One B-rep face of a CAD part: STEP entity #7803.
In plain terms, the planar face has unit normal (0, 0, 1).
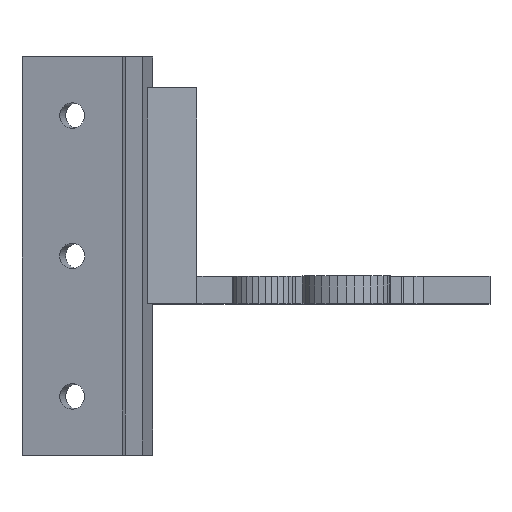
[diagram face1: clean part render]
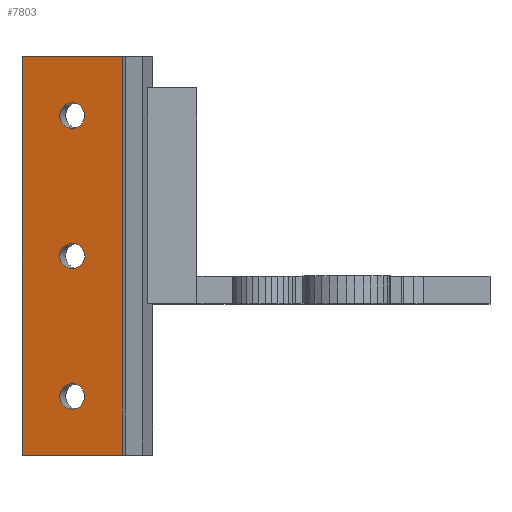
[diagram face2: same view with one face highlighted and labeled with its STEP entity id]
Its self-contained STEP definition (entity closure, numbers rounded to 3 decimals):
#7249 = VERTEX_POINT('',#7250);
#7250 = CARTESIAN_POINT('',(-9.3,-36.,5.));
#7257 = PLANE('',#7258);
#7258 = AXIS2_PLACEMENT_3D('',#7259,#7260,#7261);
#7259 = CARTESIAN_POINT('',(-9.3,-36.,0.));
#7260 = DIRECTION('',(1.,0.,0.));
#7261 = DIRECTION('',(0.,0.,1.));
#7269 = PLANE('',#7270);
#7270 = AXIS2_PLACEMENT_3D('',#7271,#7272,#7273);
#7271 = CARTESIAN_POINT('',(-9.3,-36.,0.));
#7272 = DIRECTION('',(0.,1.,0.));
#7273 = DIRECTION('',(0.,0.,1.));
#7310 = VERTEX_POINT('',#7311);
#7311 = CARTESIAN_POINT('',(-9.3,36.,5.));
#7325 = PLANE('',#7326);
#7326 = AXIS2_PLACEMENT_3D('',#7327,#7328,#7329);
#7327 = CARTESIAN_POINT('',(-9.3,36.,0.));
#7328 = DIRECTION('',(0.,1.,0.));
#7329 = DIRECTION('',(0.,0.,1.));
#7337 = EDGE_CURVE('',#7249,#7310,#7338,.T.);
#7338 = SURFACE_CURVE('',#7339,(#7343,#7350),.PCURVE_S1.);
#7339 = LINE('',#7340,#7341);
#7340 = CARTESIAN_POINT('',(-9.3,-36.,5.));
#7341 = VECTOR('',#7342,1.);
#7342 = DIRECTION('',(0.,1.,0.));
#7343 = PCURVE('',#7257,#7344);
#7344 = DEFINITIONAL_REPRESENTATION('',(#7345),#7349);
#7345 = LINE('',#7346,#7347);
#7346 = CARTESIAN_POINT('',(5.,0.));
#7347 = VECTOR('',#7348,1.);
#7348 = DIRECTION('',(0.,-1.));
#7349 = ( GEOMETRIC_REPRESENTATION_CONTEXT(2) 
PARAMETRIC_REPRESENTATION_CONTEXT() REPRESENTATION_CONTEXT('2D SPACE',''
  ) );
#7350 = PCURVE('',#7351,#7356);
#7351 = PLANE('',#7352);
#7352 = AXIS2_PLACEMENT_3D('',#7353,#7354,#7355);
#7353 = CARTESIAN_POINT('',(-9.3,-36.,5.));
#7354 = DIRECTION('',(0.,0.,1.));
#7355 = DIRECTION('',(1.,0.,0.));
#7356 = DEFINITIONAL_REPRESENTATION('',(#7357),#7361);
#7357 = LINE('',#7358,#7359);
#7358 = CARTESIAN_POINT('',(0.,0.));
#7359 = VECTOR('',#7360,1.);
#7360 = DIRECTION('',(0.,1.));
#7361 = ( GEOMETRIC_REPRESENTATION_CONTEXT(2) 
PARAMETRIC_REPRESENTATION_CONTEXT() REPRESENTATION_CONTEXT('2D SPACE',''
  ) );
#7406 = PLANE('',#7407);
#7407 = AXIS2_PLACEMENT_3D('',#7408,#7409,#7410);
#7408 = CARTESIAN_POINT('',(9.3,-36.,0.));
#7409 = DIRECTION('',(1.,0.,0.));
#7410 = DIRECTION('',(0.,0.,1.));
#7462 = CYLINDRICAL_SURFACE('',#7463,2.3);
#7463 = AXIS2_PLACEMENT_3D('',#7464,#7465,#7466);
#7464 = CARTESIAN_POINT('',(0.,-25.4,-5.));
#7465 = DIRECTION('',(-0.,0.,-1.));
#7466 = DIRECTION('',(0.,1.,0.));
#7497 = CYLINDRICAL_SURFACE('',#7498,2.3);
#7498 = AXIS2_PLACEMENT_3D('',#7499,#7500,#7501);
#7499 = CARTESIAN_POINT('',(0.,0.,-5.));
#7500 = DIRECTION('',(-0.,0.,-1.));
#7501 = DIRECTION('',(0.,1.,0.));
#7532 = CYLINDRICAL_SURFACE('',#7533,2.3);
#7533 = AXIS2_PLACEMENT_3D('',#7534,#7535,#7536);
#7534 = CARTESIAN_POINT('',(0.,25.4,-5.));
#7535 = DIRECTION('',(-0.,0.,-1.));
#7536 = DIRECTION('',(0.,1.,0.));
#7549 = VERTEX_POINT('',#7550);
#7550 = CARTESIAN_POINT('',(0.,27.7,5.));
#7571 = EDGE_CURVE('',#7549,#7549,#7572,.T.);
#7572 = SURFACE_CURVE('',#7573,(#7578,#7585),.PCURVE_S1.);
#7573 = CIRCLE('',#7574,2.3);
#7574 = AXIS2_PLACEMENT_3D('',#7575,#7576,#7577);
#7575 = CARTESIAN_POINT('',(0.,25.4,5.));
#7576 = DIRECTION('',(-0.,0.,-1.));
#7577 = DIRECTION('',(0.,1.,0.));
#7578 = PCURVE('',#7532,#7579);
#7579 = DEFINITIONAL_REPRESENTATION('',(#7580),#7584);
#7580 = LINE('',#7581,#7582);
#7581 = CARTESIAN_POINT('',(-6.283,-10.));
#7582 = VECTOR('',#7583,1.);
#7583 = DIRECTION('',(1.,-0.));
#7584 = ( GEOMETRIC_REPRESENTATION_CONTEXT(2) 
PARAMETRIC_REPRESENTATION_CONTEXT() REPRESENTATION_CONTEXT('2D SPACE',''
  ) );
#7585 = PCURVE('',#7351,#7586);
#7586 = DEFINITIONAL_REPRESENTATION('',(#7587),#7595);
#7587 = ( BOUNDED_CURVE() B_SPLINE_CURVE(2,(#7588,#7589,#7590,#7591,
#7592,#7593,#7594),.UNSPECIFIED.,.T.,.F.) B_SPLINE_CURVE_WITH_KNOTS((1,2
    ,2,2,2,1),(-2.094,0.,2.094,4.189,
6.283,8.378),.UNSPECIFIED.) CURVE() 
GEOMETRIC_REPRESENTATION_ITEM() RATIONAL_B_SPLINE_CURVE((1.,0.5,1.,0.5,
1.,0.5,1.)) REPRESENTATION_ITEM('') );
#7588 = CARTESIAN_POINT('',(9.3,63.7));
#7589 = CARTESIAN_POINT('',(13.284,63.7));
#7590 = CARTESIAN_POINT('',(11.292,60.25));
#7591 = CARTESIAN_POINT('',(9.3,56.8));
#7592 = CARTESIAN_POINT('',(7.308,60.25));
#7593 = CARTESIAN_POINT('',(5.316,63.7));
#7594 = CARTESIAN_POINT('',(9.3,63.7));
#7595 = ( GEOMETRIC_REPRESENTATION_CONTEXT(2) 
PARAMETRIC_REPRESENTATION_CONTEXT() REPRESENTATION_CONTEXT('2D SPACE',''
  ) );
#7603 = VERTEX_POINT('',#7604);
#7604 = CARTESIAN_POINT('',(0.,2.3,5.));
#7625 = EDGE_CURVE('',#7603,#7603,#7626,.T.);
#7626 = SURFACE_CURVE('',#7627,(#7632,#7639),.PCURVE_S1.);
#7627 = CIRCLE('',#7628,2.3);
#7628 = AXIS2_PLACEMENT_3D('',#7629,#7630,#7631);
#7629 = CARTESIAN_POINT('',(0.,0.,5.));
#7630 = DIRECTION('',(-0.,0.,-1.));
#7631 = DIRECTION('',(0.,1.,0.));
#7632 = PCURVE('',#7497,#7633);
#7633 = DEFINITIONAL_REPRESENTATION('',(#7634),#7638);
#7634 = LINE('',#7635,#7636);
#7635 = CARTESIAN_POINT('',(-6.283,-10.));
#7636 = VECTOR('',#7637,1.);
#7637 = DIRECTION('',(1.,-0.));
#7638 = ( GEOMETRIC_REPRESENTATION_CONTEXT(2) 
PARAMETRIC_REPRESENTATION_CONTEXT() REPRESENTATION_CONTEXT('2D SPACE',''
  ) );
#7639 = PCURVE('',#7351,#7640);
#7640 = DEFINITIONAL_REPRESENTATION('',(#7641),#7649);
#7641 = ( BOUNDED_CURVE() B_SPLINE_CURVE(2,(#7642,#7643,#7644,#7645,
#7646,#7647,#7648),.UNSPECIFIED.,.T.,.F.) B_SPLINE_CURVE_WITH_KNOTS((1,2
    ,2,2,2,1),(-2.094,0.,2.094,4.189,
6.283,8.378),.UNSPECIFIED.) CURVE() 
GEOMETRIC_REPRESENTATION_ITEM() RATIONAL_B_SPLINE_CURVE((1.,0.5,1.,0.5,
1.,0.5,1.)) REPRESENTATION_ITEM('') );
#7642 = CARTESIAN_POINT('',(9.3,38.3));
#7643 = CARTESIAN_POINT('',(13.284,38.3));
#7644 = CARTESIAN_POINT('',(11.292,34.85));
#7645 = CARTESIAN_POINT('',(9.3,31.4));
#7646 = CARTESIAN_POINT('',(7.308,34.85));
#7647 = CARTESIAN_POINT('',(5.316,38.3));
#7648 = CARTESIAN_POINT('',(9.3,38.3));
#7649 = ( GEOMETRIC_REPRESENTATION_CONTEXT(2) 
PARAMETRIC_REPRESENTATION_CONTEXT() REPRESENTATION_CONTEXT('2D SPACE',''
  ) );
#7657 = VERTEX_POINT('',#7658);
#7658 = CARTESIAN_POINT('',(0.,-23.1,5.));
#7679 = EDGE_CURVE('',#7657,#7657,#7680,.T.);
#7680 = SURFACE_CURVE('',#7681,(#7686,#7693),.PCURVE_S1.);
#7681 = CIRCLE('',#7682,2.3);
#7682 = AXIS2_PLACEMENT_3D('',#7683,#7684,#7685);
#7683 = CARTESIAN_POINT('',(0.,-25.4,5.));
#7684 = DIRECTION('',(-0.,0.,-1.));
#7685 = DIRECTION('',(0.,1.,0.));
#7686 = PCURVE('',#7462,#7687);
#7687 = DEFINITIONAL_REPRESENTATION('',(#7688),#7692);
#7688 = LINE('',#7689,#7690);
#7689 = CARTESIAN_POINT('',(-6.283,-10.));
#7690 = VECTOR('',#7691,1.);
#7691 = DIRECTION('',(1.,-0.));
#7692 = ( GEOMETRIC_REPRESENTATION_CONTEXT(2) 
PARAMETRIC_REPRESENTATION_CONTEXT() REPRESENTATION_CONTEXT('2D SPACE',''
  ) );
#7693 = PCURVE('',#7351,#7694);
#7694 = DEFINITIONAL_REPRESENTATION('',(#7695),#7703);
#7695 = ( BOUNDED_CURVE() B_SPLINE_CURVE(2,(#7696,#7697,#7698,#7699,
#7700,#7701,#7702),.UNSPECIFIED.,.T.,.F.) B_SPLINE_CURVE_WITH_KNOTS((1,2
    ,2,2,2,1),(-2.094,0.,2.094,4.189,
6.283,8.378),.UNSPECIFIED.) CURVE() 
GEOMETRIC_REPRESENTATION_ITEM() RATIONAL_B_SPLINE_CURVE((1.,0.5,1.,0.5,
1.,0.5,1.)) REPRESENTATION_ITEM('') );
#7696 = CARTESIAN_POINT('',(9.3,12.9));
#7697 = CARTESIAN_POINT('',(13.284,12.9));
#7698 = CARTESIAN_POINT('',(11.292,9.45));
#7699 = CARTESIAN_POINT('',(9.3,6.));
#7700 = CARTESIAN_POINT('',(7.308,9.45));
#7701 = CARTESIAN_POINT('',(5.316,12.9));
#7702 = CARTESIAN_POINT('',(9.3,12.9));
#7703 = ( GEOMETRIC_REPRESENTATION_CONTEXT(2) 
PARAMETRIC_REPRESENTATION_CONTEXT() REPRESENTATION_CONTEXT('2D SPACE',''
  ) );
#7710 = VERTEX_POINT('',#7711);
#7711 = CARTESIAN_POINT('',(9.3,-36.,5.));
#7734 = VERTEX_POINT('',#7735);
#7735 = CARTESIAN_POINT('',(9.3,36.,5.));
#7756 = EDGE_CURVE('',#7710,#7734,#7757,.T.);
#7757 = SURFACE_CURVE('',#7758,(#7762,#7769),.PCURVE_S1.);
#7758 = LINE('',#7759,#7760);
#7759 = CARTESIAN_POINT('',(9.3,-36.,5.));
#7760 = VECTOR('',#7761,1.);
#7761 = DIRECTION('',(0.,1.,0.));
#7762 = PCURVE('',#7406,#7763);
#7763 = DEFINITIONAL_REPRESENTATION('',(#7764),#7768);
#7764 = LINE('',#7765,#7766);
#7765 = CARTESIAN_POINT('',(5.,0.));
#7766 = VECTOR('',#7767,1.);
#7767 = DIRECTION('',(0.,-1.));
#7768 = ( GEOMETRIC_REPRESENTATION_CONTEXT(2) 
PARAMETRIC_REPRESENTATION_CONTEXT() REPRESENTATION_CONTEXT('2D SPACE',''
  ) );
#7769 = PCURVE('',#7351,#7770);
#7770 = DEFINITIONAL_REPRESENTATION('',(#7771),#7775);
#7771 = LINE('',#7772,#7773);
#7772 = CARTESIAN_POINT('',(18.6,0.));
#7773 = VECTOR('',#7774,1.);
#7774 = DIRECTION('',(0.,1.));
#7775 = ( GEOMETRIC_REPRESENTATION_CONTEXT(2) 
PARAMETRIC_REPRESENTATION_CONTEXT() REPRESENTATION_CONTEXT('2D SPACE',''
  ) );
#7782 = EDGE_CURVE('',#7310,#7734,#7783,.T.);
#7783 = SURFACE_CURVE('',#7784,(#7788,#7795),.PCURVE_S1.);
#7784 = LINE('',#7785,#7786);
#7785 = CARTESIAN_POINT('',(-9.3,36.,5.));
#7786 = VECTOR('',#7787,1.);
#7787 = DIRECTION('',(1.,0.,0.));
#7788 = PCURVE('',#7325,#7789);
#7789 = DEFINITIONAL_REPRESENTATION('',(#7790),#7794);
#7790 = LINE('',#7791,#7792);
#7791 = CARTESIAN_POINT('',(5.,0.));
#7792 = VECTOR('',#7793,1.);
#7793 = DIRECTION('',(0.,1.));
#7794 = ( GEOMETRIC_REPRESENTATION_CONTEXT(2) 
PARAMETRIC_REPRESENTATION_CONTEXT() REPRESENTATION_CONTEXT('2D SPACE',''
  ) );
#7795 = PCURVE('',#7351,#7796);
#7796 = DEFINITIONAL_REPRESENTATION('',(#7797),#7801);
#7797 = LINE('',#7798,#7799);
#7798 = CARTESIAN_POINT('',(0.,72.));
#7799 = VECTOR('',#7800,1.);
#7800 = DIRECTION('',(1.,0.));
#7801 = ( GEOMETRIC_REPRESENTATION_CONTEXT(2) 
PARAMETRIC_REPRESENTATION_CONTEXT() REPRESENTATION_CONTEXT('2D SPACE',''
  ) );
#7803 = ADVANCED_FACE('',(#7804,#7830,#7833,#7836),#7351,.T.);
#7804 = FACE_BOUND('',#7805,.T.);
#7805 = EDGE_LOOP('',(#7806,#7807,#7828,#7829));
#7806 = ORIENTED_EDGE('',*,*,#7337,.F.);
#7807 = ORIENTED_EDGE('',*,*,#7808,.T.);
#7808 = EDGE_CURVE('',#7249,#7710,#7809,.T.);
#7809 = SURFACE_CURVE('',#7810,(#7814,#7821),.PCURVE_S1.);
#7810 = LINE('',#7811,#7812);
#7811 = CARTESIAN_POINT('',(-9.3,-36.,5.));
#7812 = VECTOR('',#7813,1.);
#7813 = DIRECTION('',(1.,0.,0.));
#7814 = PCURVE('',#7351,#7815);
#7815 = DEFINITIONAL_REPRESENTATION('',(#7816),#7820);
#7816 = LINE('',#7817,#7818);
#7817 = CARTESIAN_POINT('',(0.,0.));
#7818 = VECTOR('',#7819,1.);
#7819 = DIRECTION('',(1.,0.));
#7820 = ( GEOMETRIC_REPRESENTATION_CONTEXT(2) 
PARAMETRIC_REPRESENTATION_CONTEXT() REPRESENTATION_CONTEXT('2D SPACE',''
  ) );
#7821 = PCURVE('',#7269,#7822);
#7822 = DEFINITIONAL_REPRESENTATION('',(#7823),#7827);
#7823 = LINE('',#7824,#7825);
#7824 = CARTESIAN_POINT('',(5.,0.));
#7825 = VECTOR('',#7826,1.);
#7826 = DIRECTION('',(0.,1.));
#7827 = ( GEOMETRIC_REPRESENTATION_CONTEXT(2) 
PARAMETRIC_REPRESENTATION_CONTEXT() REPRESENTATION_CONTEXT('2D SPACE',''
  ) );
#7828 = ORIENTED_EDGE('',*,*,#7756,.T.);
#7829 = ORIENTED_EDGE('',*,*,#7782,.F.);
#7830 = FACE_BOUND('',#7831,.T.);
#7831 = EDGE_LOOP('',(#7832));
#7832 = ORIENTED_EDGE('',*,*,#7679,.T.);
#7833 = FACE_BOUND('',#7834,.T.);
#7834 = EDGE_LOOP('',(#7835));
#7835 = ORIENTED_EDGE('',*,*,#7625,.T.);
#7836 = FACE_BOUND('',#7837,.T.);
#7837 = EDGE_LOOP('',(#7838));
#7838 = ORIENTED_EDGE('',*,*,#7571,.T.);
